VERSION 5.7 ;
  NOWIREEXTENSIONATPIN ON ;
  DIVIDERCHAR "/" ;
  BUSBITCHARS "[]" ;
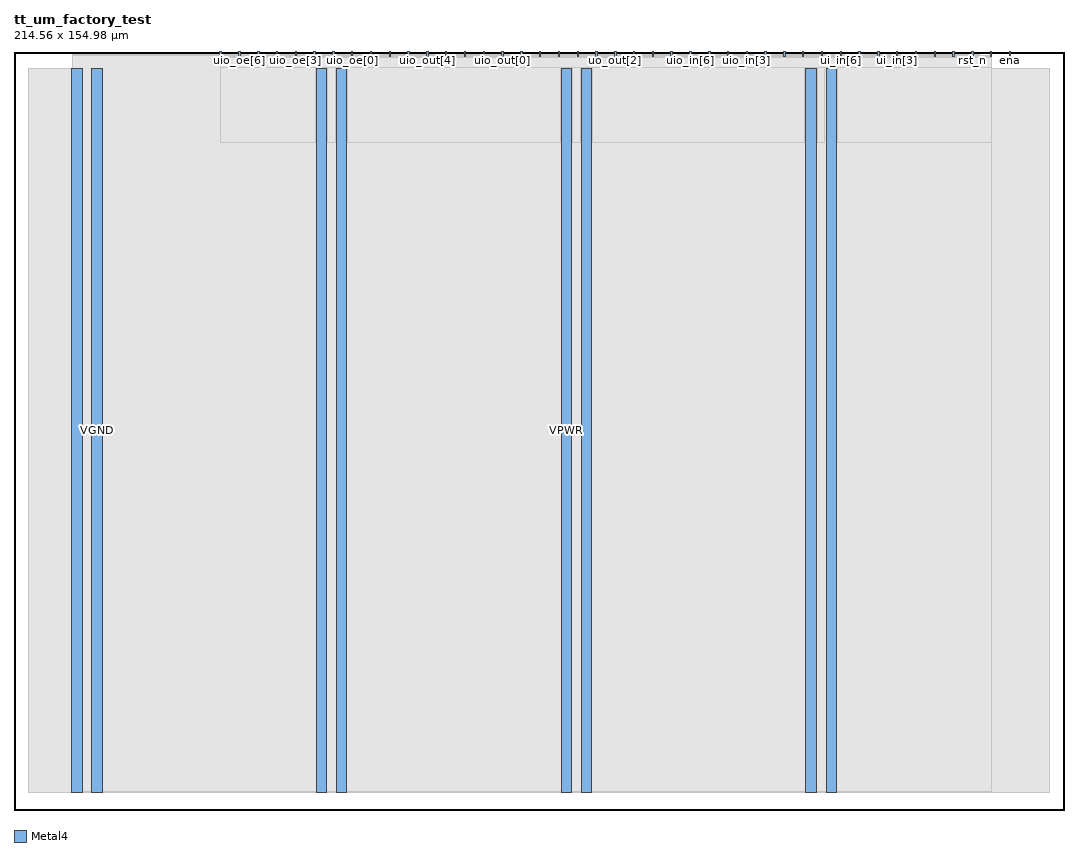
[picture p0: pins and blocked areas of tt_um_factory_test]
MACRO tt_um_factory_test
  CLASS BLOCK ;
  FOREIGN tt_um_factory_test ;
  ORIGIN 0.000 0.000 ;
  SIZE 214.560 BY 154.980 ;
  PIN VGND
    DIRECTION INOUT ;
    USE GROUND ;
    PORT
      LAYER Metal4 ;
        RECT 15.930 3.560 18.030 151.420 ;
    END
    PORT
      LAYER Metal4 ;
        RECT 65.930 3.560 68.030 151.420 ;
    END
    PORT
      LAYER Metal4 ;
        RECT 115.930 3.560 118.030 151.420 ;
    END
    PORT
      LAYER Metal4 ;
        RECT 165.930 3.560 168.030 151.420 ;
    END
  END VGND
  PIN VPWR
    DIRECTION INOUT ;
    USE POWER ;
    PORT
      LAYER Metal4 ;
        RECT 11.830 3.560 13.930 151.420 ;
    END
    PORT
      LAYER Metal4 ;
        RECT 61.830 3.560 63.930 151.420 ;
    END
    PORT
      LAYER Metal4 ;
        RECT 111.830 3.560 113.930 151.420 ;
    END
    PORT
      LAYER Metal4 ;
        RECT 161.830 3.560 163.930 151.420 ;
    END
  END VPWR
  PIN clk
    DIRECTION INPUT ;
    USE SIGNAL ;
    ANTENNAGATEAREA 0.725400 ;
    PORT
      LAYER Metal4 ;
        RECT 199.530 153.980 199.830 154.980 ;
    END
  END clk
  PIN ena
    DIRECTION INPUT ;
    USE SIGNAL ;
    PORT
      LAYER Metal4 ;
        RECT 203.370 153.980 203.670 154.980 ;
    END
  END ena
  PIN rst_n
    DIRECTION INPUT ;
    USE SIGNAL ;
    ANTENNAGATEAREA 0.180700 ;
    PORT
      LAYER Metal4 ;
        RECT 195.690 153.980 195.990 154.980 ;
    END
  END rst_n
  PIN ui_in[0]
    DIRECTION INPUT ;
    USE SIGNAL ;
    ANTENNAGATEAREA 0.180700 ;
    PORT
      LAYER Metal4 ;
        RECT 191.850 153.980 192.150 154.980 ;
    END
  END ui_in[0]
  PIN ui_in[1]
    DIRECTION INPUT ;
    USE SIGNAL ;
    ANTENNAGATEAREA 0.180700 ;
    PORT
      LAYER Metal4 ;
        RECT 188.010 153.980 188.310 154.980 ;
    END
  END ui_in[1]
  PIN ui_in[2]
    DIRECTION INPUT ;
    USE SIGNAL ;
    ANTENNAGATEAREA 0.180700 ;
    PORT
      LAYER Metal4 ;
        RECT 184.170 153.980 184.470 154.980 ;
    END
  END ui_in[2]
  PIN ui_in[3]
    DIRECTION INPUT ;
    USE SIGNAL ;
    ANTENNAGATEAREA 0.180700 ;
    PORT
      LAYER Metal4 ;
        RECT 180.330 153.980 180.630 154.980 ;
    END
  END ui_in[3]
  PIN ui_in[4]
    DIRECTION INPUT ;
    USE SIGNAL ;
    ANTENNAGATEAREA 0.180700 ;
    PORT
      LAYER Metal4 ;
        RECT 176.490 153.980 176.790 154.980 ;
    END
  END ui_in[4]
  PIN ui_in[5]
    DIRECTION INPUT ;
    USE SIGNAL ;
    ANTENNAGATEAREA 0.180700 ;
    PORT
      LAYER Metal4 ;
        RECT 172.650 153.980 172.950 154.980 ;
    END
  END ui_in[5]
  PIN ui_in[6]
    DIRECTION INPUT ;
    USE SIGNAL ;
    ANTENNAGATEAREA 0.180700 ;
    PORT
      LAYER Metal4 ;
        RECT 168.810 153.980 169.110 154.980 ;
    END
  END ui_in[6]
  PIN ui_in[7]
    DIRECTION INPUT ;
    USE SIGNAL ;
    ANTENNAGATEAREA 0.180700 ;
    PORT
      LAYER Metal4 ;
        RECT 164.970 153.980 165.270 154.980 ;
    END
  END ui_in[7]
  PIN uio_in[0]
    DIRECTION INPUT ;
    USE SIGNAL ;
    ANTENNAGATEAREA 0.180700 ;
    PORT
      LAYER Metal4 ;
        RECT 161.130 153.980 161.430 154.980 ;
    END
  END uio_in[0]
  PIN uio_in[1]
    DIRECTION INPUT ;
    USE SIGNAL ;
    ANTENNAGATEAREA 0.180700 ;
    PORT
      LAYER Metal4 ;
        RECT 157.290 153.980 157.590 154.980 ;
    END
  END uio_in[1]
  PIN uio_in[2]
    DIRECTION INPUT ;
    USE SIGNAL ;
    ANTENNAGATEAREA 0.180700 ;
    PORT
      LAYER Metal4 ;
        RECT 153.450 153.980 153.750 154.980 ;
    END
  END uio_in[2]
  PIN uio_in[3]
    DIRECTION INPUT ;
    USE SIGNAL ;
    ANTENNAGATEAREA 0.180700 ;
    PORT
      LAYER Metal4 ;
        RECT 149.610 153.980 149.910 154.980 ;
    END
  END uio_in[3]
  PIN uio_in[4]
    DIRECTION INPUT ;
    USE SIGNAL ;
    ANTENNAGATEAREA 0.180700 ;
    PORT
      LAYER Metal4 ;
        RECT 145.770 153.980 146.070 154.980 ;
    END
  END uio_in[4]
  PIN uio_in[5]
    DIRECTION INPUT ;
    USE SIGNAL ;
    ANTENNAGATEAREA 0.180700 ;
    PORT
      LAYER Metal4 ;
        RECT 141.930 153.980 142.230 154.980 ;
    END
  END uio_in[5]
  PIN uio_in[6]
    DIRECTION INPUT ;
    USE SIGNAL ;
    ANTENNAGATEAREA 0.180700 ;
    PORT
      LAYER Metal4 ;
        RECT 138.090 153.980 138.390 154.980 ;
    END
  END uio_in[6]
  PIN uio_in[7]
    DIRECTION INPUT ;
    USE SIGNAL ;
    ANTENNAGATEAREA 0.180700 ;
    PORT
      LAYER Metal4 ;
        RECT 134.250 153.980 134.550 154.980 ;
    END
  END uio_in[7]
  PIN uio_oe[0]
    DIRECTION OUTPUT ;
    USE SIGNAL ;
    ANTENNADIFFAREA 0.708600 ;
    PORT
      LAYER Metal4 ;
        RECT 68.970 153.980 69.270 154.980 ;
    END
  END uio_oe[0]
  PIN uio_oe[1]
    DIRECTION OUTPUT ;
    USE SIGNAL ;
    ANTENNADIFFAREA 0.708600 ;
    PORT
      LAYER Metal4 ;
        RECT 65.130 153.980 65.430 154.980 ;
    END
  END uio_oe[1]
  PIN uio_oe[2]
    DIRECTION OUTPUT ;
    USE SIGNAL ;
    ANTENNADIFFAREA 0.708600 ;
    PORT
      LAYER Metal4 ;
        RECT 61.290 153.980 61.590 154.980 ;
    END
  END uio_oe[2]
  PIN uio_oe[3]
    DIRECTION OUTPUT ;
    USE SIGNAL ;
    ANTENNADIFFAREA 0.708600 ;
    PORT
      LAYER Metal4 ;
        RECT 57.450 153.980 57.750 154.980 ;
    END
  END uio_oe[3]
  PIN uio_oe[4]
    DIRECTION OUTPUT ;
    USE SIGNAL ;
    ANTENNADIFFAREA 0.708600 ;
    PORT
      LAYER Metal4 ;
        RECT 53.610 153.980 53.910 154.980 ;
    END
  END uio_oe[4]
  PIN uio_oe[5]
    DIRECTION OUTPUT ;
    USE SIGNAL ;
    ANTENNADIFFAREA 0.708600 ;
    PORT
      LAYER Metal4 ;
        RECT 49.770 153.980 50.070 154.980 ;
    END
  END uio_oe[5]
  PIN uio_oe[6]
    DIRECTION OUTPUT ;
    USE SIGNAL ;
    ANTENNADIFFAREA 0.708600 ;
    PORT
      LAYER Metal4 ;
        RECT 45.930 153.980 46.230 154.980 ;
    END
  END uio_oe[6]
  PIN uio_oe[7]
    DIRECTION OUTPUT ;
    USE SIGNAL ;
    ANTENNAGATEAREA 1.506700 ;
    ANTENNADIFFAREA 0.632400 ;
    PORT
      LAYER Metal4 ;
        RECT 42.090 153.980 42.390 154.980 ;
    END
  END uio_oe[7]
  PIN uio_out[0]
    DIRECTION OUTPUT ;
    USE SIGNAL ;
    ANTENNADIFFAREA 0.632400 ;
    PORT
      LAYER Metal4 ;
        RECT 99.690 153.980 99.990 154.980 ;
    END
  END uio_out[0]
  PIN uio_out[1]
    DIRECTION OUTPUT ;
    USE SIGNAL ;
    ANTENNAGATEAREA 0.241800 ;
    ANTENNADIFFAREA 0.632400 ;
    PORT
      LAYER Metal4 ;
        RECT 95.850 153.980 96.150 154.980 ;
    END
  END uio_out[1]
  PIN uio_out[2]
    DIRECTION OUTPUT ;
    USE SIGNAL ;
    ANTENNAGATEAREA 0.241800 ;
    ANTENNADIFFAREA 0.632400 ;
    PORT
      LAYER Metal4 ;
        RECT 92.010 153.980 92.310 154.980 ;
    END
  END uio_out[2]
  PIN uio_out[3]
    DIRECTION OUTPUT ;
    USE SIGNAL ;
    ANTENNAGATEAREA 0.241800 ;
    ANTENNADIFFAREA 0.632400 ;
    PORT
      LAYER Metal4 ;
        RECT 88.170 153.980 88.470 154.980 ;
    END
  END uio_out[3]
  PIN uio_out[4]
    DIRECTION OUTPUT ;
    USE SIGNAL ;
    ANTENNAGATEAREA 0.241800 ;
    ANTENNADIFFAREA 0.632400 ;
    PORT
      LAYER Metal4 ;
        RECT 84.330 153.980 84.630 154.980 ;
    END
  END uio_out[4]
  PIN uio_out[5]
    DIRECTION OUTPUT ;
    USE SIGNAL ;
    ANTENNAGATEAREA 0.241800 ;
    ANTENNADIFFAREA 0.632400 ;
    PORT
      LAYER Metal4 ;
        RECT 80.490 153.980 80.790 154.980 ;
    END
  END uio_out[5]
  PIN uio_out[6]
    DIRECTION OUTPUT ;
    USE SIGNAL ;
    ANTENNAGATEAREA 0.241800 ;
    ANTENNADIFFAREA 0.632400 ;
    PORT
      LAYER Metal4 ;
        RECT 76.650 153.980 76.950 154.980 ;
    END
  END uio_out[6]
  PIN uio_out[7]
    DIRECTION OUTPUT ;
    USE SIGNAL ;
    ANTENNAGATEAREA 0.241800 ;
    ANTENNADIFFAREA 0.632400 ;
    PORT
      LAYER Metal4 ;
        RECT 72.810 153.980 73.110 154.980 ;
    END
  END uio_out[7]
  PIN uo_out[0]
    DIRECTION OUTPUT ;
    USE SIGNAL ;
    ANTENNADIFFAREA 0.662000 ;
    PORT
      LAYER Metal4 ;
        RECT 130.410 153.980 130.710 154.980 ;
    END
  END uo_out[0]
  PIN uo_out[1]
    DIRECTION OUTPUT ;
    USE SIGNAL ;
    ANTENNADIFFAREA 0.958400 ;
    PORT
      LAYER Metal4 ;
        RECT 126.570 153.980 126.870 154.980 ;
    END
  END uo_out[1]
  PIN uo_out[2]
    DIRECTION OUTPUT ;
    USE SIGNAL ;
    ANTENNADIFFAREA 0.958400 ;
    PORT
      LAYER Metal4 ;
        RECT 122.730 153.980 123.030 154.980 ;
    END
  END uo_out[2]
  PIN uo_out[3]
    DIRECTION OUTPUT ;
    USE SIGNAL ;
    ANTENNADIFFAREA 0.958400 ;
    PORT
      LAYER Metal4 ;
        RECT 118.890 153.980 119.190 154.980 ;
    END
  END uo_out[3]
  PIN uo_out[4]
    DIRECTION OUTPUT ;
    USE SIGNAL ;
    ANTENNADIFFAREA 0.958400 ;
    PORT
      LAYER Metal4 ;
        RECT 115.050 153.980 115.350 154.980 ;
    END
  END uo_out[4]
  PIN uo_out[5]
    DIRECTION OUTPUT ;
    USE SIGNAL ;
    ANTENNADIFFAREA 0.958400 ;
    PORT
      LAYER Metal4 ;
        RECT 111.210 153.980 111.510 154.980 ;
    END
  END uo_out[5]
  PIN uo_out[6]
    DIRECTION OUTPUT ;
    USE SIGNAL ;
    ANTENNADIFFAREA 0.958400 ;
    PORT
      LAYER Metal4 ;
        RECT 107.370 153.980 107.670 154.980 ;
    END
  END uo_out[6]
  PIN uo_out[7]
    DIRECTION OUTPUT ;
    USE SIGNAL ;
    ANTENNADIFFAREA 0.958400 ;
    PORT
      LAYER Metal4 ;
        RECT 103.530 153.980 103.830 154.980 ;
    END
  END uo_out[7]
  OBS
      LAYER GatPoly ;
        RECT 2.880 3.630 211.680 151.350 ;
      LAYER Metal1 ;
        RECT 2.880 3.560 211.680 151.420 ;
      LAYER Metal2 ;
        RECT 11.960 3.635 197.385 154.285 ;
      LAYER Metal3 ;
        RECT 11.915 3.680 199.825 154.240 ;
      LAYER Metal4 ;
        RECT 42.600 153.770 45.720 153.980 ;
        RECT 46.440 153.770 49.560 153.980 ;
        RECT 50.280 153.770 53.400 153.980 ;
        RECT 54.120 153.770 57.240 153.980 ;
        RECT 57.960 153.770 61.080 153.980 ;
        RECT 61.800 153.770 64.920 153.980 ;
        RECT 65.640 153.770 68.760 153.980 ;
        RECT 69.480 153.770 72.600 153.980 ;
        RECT 73.320 153.770 76.440 153.980 ;
        RECT 77.160 153.770 80.280 153.980 ;
        RECT 81.000 153.770 84.120 153.980 ;
        RECT 84.840 153.770 87.960 153.980 ;
        RECT 88.680 153.770 91.800 153.980 ;
        RECT 92.520 153.770 95.640 153.980 ;
        RECT 96.360 153.770 99.480 153.980 ;
        RECT 100.200 153.770 103.320 153.980 ;
        RECT 104.040 153.770 107.160 153.980 ;
        RECT 107.880 153.770 111.000 153.980 ;
        RECT 111.720 153.770 114.840 153.980 ;
        RECT 115.560 153.770 118.680 153.980 ;
        RECT 119.400 153.770 122.520 153.980 ;
        RECT 123.240 153.770 126.360 153.980 ;
        RECT 127.080 153.770 130.200 153.980 ;
        RECT 130.920 153.770 134.040 153.980 ;
        RECT 134.760 153.770 137.880 153.980 ;
        RECT 138.600 153.770 141.720 153.980 ;
        RECT 142.440 153.770 145.560 153.980 ;
        RECT 146.280 153.770 149.400 153.980 ;
        RECT 150.120 153.770 153.240 153.980 ;
        RECT 153.960 153.770 157.080 153.980 ;
        RECT 157.800 153.770 160.920 153.980 ;
        RECT 161.640 153.770 164.760 153.980 ;
        RECT 165.480 153.770 168.600 153.980 ;
        RECT 169.320 153.770 172.440 153.980 ;
        RECT 173.160 153.770 176.280 153.980 ;
        RECT 177.000 153.770 180.120 153.980 ;
        RECT 180.840 153.770 183.960 153.980 ;
        RECT 184.680 153.770 187.800 153.980 ;
        RECT 188.520 153.770 191.640 153.980 ;
        RECT 192.360 153.770 195.480 153.980 ;
        RECT 196.200 153.770 199.320 153.980 ;
        RECT 42.140 151.630 199.780 153.770 ;
        RECT 42.140 136.355 61.620 151.630 ;
        RECT 64.140 136.355 65.720 151.630 ;
        RECT 68.240 136.355 111.620 151.630 ;
        RECT 114.140 136.355 115.720 151.630 ;
        RECT 118.240 136.355 161.620 151.630 ;
        RECT 164.140 136.355 165.720 151.630 ;
        RECT 168.240 136.355 199.780 151.630 ;
  END
END tt_um_factory_test
END LIBRARY

